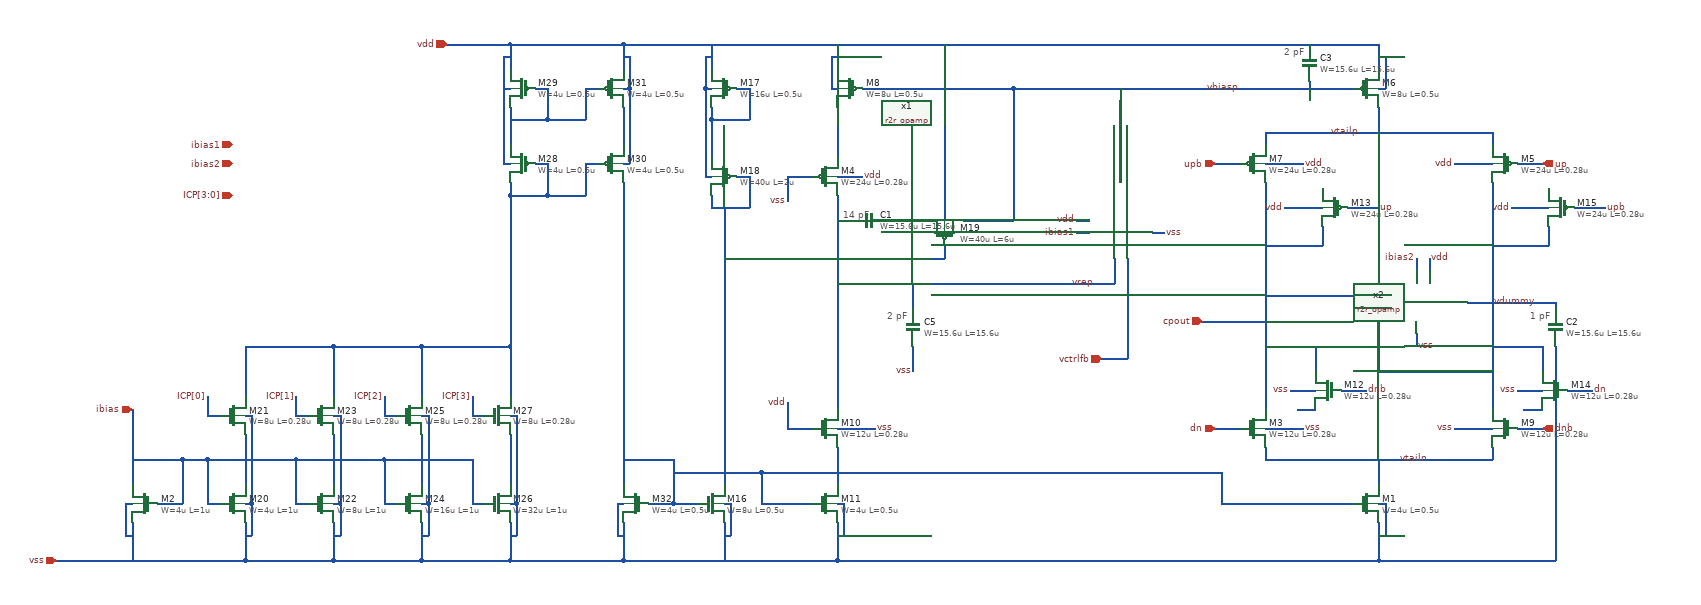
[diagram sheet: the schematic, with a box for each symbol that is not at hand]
v {xschem version=3.4.5 file_version=1.2
}
G {}
K {}
V {}
S {}
E {}
T {2 pF} 1260 -420 0 0 0.2 0.2 {}
T {1 pF} 2280 -420 0 0 0.2 0.2 {}
T {2 pF} 1890 -840 0 0 0.2 0.2 {}
T {14 pF} 1190 -580 0 0 0.2 0.2 {}
N 60 -260 60 -140 {
lab=ibias}
N 1960 -110 2000 -110 {
lab=#net1}
N 60 -80 60 -20 {
lab=vss}
N 2040 -80 2040 -20 {
lab=vss}
N 50 -110 60 -110 {
lab=vss}
N 50 -110 50 -60 {
lab=vss}
N 50 -60 60 -60 {
lab=vss}
N 2040 -110 2050 -110 {
lab=vss}
N 2050 -110 2050 -60 {
lab=vss}
N 2040 -60 2050 -60 {
lab=vss}
N 2040 -840 2040 -800 {
lab=vdd}
N 2040 -770 2050 -770 {
lab=vdd}
N 2050 -820 2050 -770 {
lab=vdd}
N 2040 -820 2050 -820 {
lab=vdd}
N 1940 -770 2000 -770 {
lab=vbiasp}
N 1860 -650 1870 -650 {
lab=vdd}
N -60 -20 20 -20 {
lab=vss}
N 1180 -840 1180 -800 {
lab=vdd}
N 1170 -770 1180 -770 {
lab=vdd}
N 1170 -820 1170 -770 {
lab=vdd}
N 1170 -820 1180 -820 {
lab=vdd}
N 1220 -770 1280 -770 {
lab=vbiasp}
N 1680 -840 2040 -840 {
lab=vdd}
N 1380 -840 1480 -840 {
lab=vdd}
N 1680 -770 1940 -770 {
lab=vbiasp}
N 1280 -840 1380 -840 {
lab=vdd}
N 1480 -840 1680 -840 {
lab=vdd}
N 1480 -770 1680 -770 {
lab=vbiasp}
N 2210 -650 2220 -650 {
lab=vdd}
N 1860 -700 1860 -680 {
lab=vtailp}
N 1860 -700 2220 -700 {
lab=vtailp}
N 2220 -700 2220 -680 {
lab=vtailp}
N 2040 -740 2040 -700 {
lab=vtailp}
N 1870 -650 1920 -650 {
lab=vdd}
N 2160 -650 2210 -650 {
lab=vdd}
N 1860 -200 1860 -180 {
lab=vtailn}
N 1860 -180 2220 -180 {
lab=vtailn}
N 2220 -200 2220 -180 {
lab=vtailn}
N 2040 -180 2040 -140 {
lab=vtailn}
N 1860 -620 1860 -260 {
lab=cpout}
N 2220 -620 2220 -260 {
lab=vdummy}
N 1860 -230 1920 -230 {
lab=vss}
N 2160 -230 2220 -230 {
lab=vss}
N 2180 -430 2220 -430 {
lab=vdummy}
N 2100 -380 2100 -360 {
lab=vss}
N 2100 -500 2100 -480 {
lab=ibias2}
N 2120 -500 2120 -480 {
lab=vdd}
N 1860 -440 2060 -440 {
lab=cpout}
N 2040 -420 2060 -420 {
lab=vdummy}
N 2040 -420 2040 -320 {
lab=vdummy}
N 2040 -320 2220 -320 {
lab=vdummy}
N 1630 -770 1630 -620 {
lab=vbiasp}
N 1180 -630 1190 -630 {
lab=vdd}
N 1180 -230 1240 -230 {
lab=vss}
N 1180 -600 1180 -260 {
lab=vrep}
N 1180 -740 1180 -660 {
lab=#net2}
N 1100 -110 1140 -110 {
lab=#net1}
N 1180 -80 1180 -20 {
lab=vss}
N 1180 -110 1190 -110 {
lab=vss}
N 1190 -110 1190 -60 {
lab=vss}
N 1180 -60 1190 -60 {
lab=vss}
N 1180 -180 1180 -140 {
lab=#net3}
N 1180 -200 1180 -180 {
lab=#net3}
N 1100 -230 1140 -230 {
lab=vdd}
N 1100 -270 1100 -230 {
lab=vdd}
N 1100 -630 1140 -630 {
lab=vss}
N 1100 -630 1100 -590 {
lab=vss}
N 1620 -500 1620 -460 {
lab=vrep}
N 1260 -460 1420 -460 {
lab=vrep}
N 1640 -500 1640 -460 {
lab=vctrlfb}
N 1380 -20 2040 -20 {
lab=vss}
N 1180 -20 1380 -20 {
lab=vss}
N 60 -180 140 -180 {
lab=ibias}
N 140 -180 140 -110 {
lab=ibias}
N 100 -110 140 -110 {
lab=ibias}
N 1060 -110 1100 -110 {
lab=#net1}
N 1060 -160 1590 -160 {
lab=#net1}
N 1790 -160 1790 -110 {
lab=#net1}
N 1790 -110 1960 -110 {
lab=#net1}
N 1900 -290 1940 -290 {
lab=vss}
N 1940 -360 1940 -320 {
lab=cpout}
N 1980 -290 2020 -290 {
lab=dnb}
N 1950 -550 1950 -520 {
lab=cpout}
N 1990 -580 2040 -580 {
lab=up}
N 1890 -580 1950 -580 {
lab=vdd}
N 1780 -230 1820 -230 {
lab=dn}
N 1780 -650 1820 -650 {
lab=upb}
N 2260 -650 2300 -650 {
lab=up}
N 2260 -230 2300 -230 {
lab=dnb}
N 1560 -560 1580 -560 {
lab=vdd}
N 1560 -540 1580 -540 {
lab=ibias1}
N 1680 -540 1700 -540 {
lab=vss}
N 1760 -400 1860 -400 {
lab=cpout}
N 2040 -20 2140 -20 {
lab=vss}
N 2320 -430 2320 -420 {
lab=vdummy}
N 2220 -430 2320 -430 {
lab=vdummy}
N 2320 -360 2320 -20 {
lab=vss}
N 2140 -20 2320 -20 {
lab=vss}
N 1640 -460 1640 -340 {
lab=vctrlfb}
N 1600 -340 1640 -340 {
lab=vctrlfb}
N 1180 -460 1260 -460 {
lab=vrep}
N 1190 -630 1220 -630 {
lab=vdd}
N 1180 -560 1200 -560 {
lab=vrep}
N 1930 -780 1930 -770 {
lab=vbiasp}
N 1910 -260 1940 -260 {
lab=#net4}
N 940 -840 1000 -840 {
lab=vdd}
N 1000 -840 1280 -840 {
lab=vdd}
N 2260 -290 2300 -290 {
lab=vss}
N 2300 -360 2300 -320 {
lab=vdummy}
N 2340 -290 2380 -290 {
lab=dn}
N 2310 -550 2310 -520 {
lab=vdummy}
N 2350 -580 2400 -580 {
lab=upb}
N 2250 -580 2310 -580 {
lab=vdd}
N 2270 -260 2300 -260 {
lab=#net5}
N 1920 -520 1950 -520 {
lab=cpout}
N 2280 -520 2310 -520 {
lab=vdummy}
N 1910 -360 1940 -360 {
lab=cpout}
N 2270 -360 2300 -360 {
lab=vdummy}
N 1860 -360 1910 -360 {
lab=cpout}
N 1860 -520 1920 -520 {
lab=cpout}
N 2220 -520 2280 -520 {
lab=vdummy}
N 2220 -360 2270 -360 {
lab=vdummy}
N 840 -20 1180 -20 {
lab=vss}
N 1590 -160 1790 -160 {
lab=#net1}
N 1420 -460 1620 -460 {
lab=vrep}
N 1000 -80 1000 -20 {
lab=vss}
N 1000 -110 1010 -110 {
lab=vss}
N 1010 -110 1010 -60 {
lab=vss}
N 1000 -60 1010 -60 {
lab=vss}
N 1000 -180 1000 -140 {
lab=#net6}
N 980 -840 980 -800 {
lab=vdd}
N 970 -770 980 -770 {
lab=vdd}
N 970 -820 970 -770 {
lab=vdd}
N 970 -820 980 -820 {
lab=vdd}
N 980 -740 980 -720 {
lab=#net7}
N 980 -720 1040 -720 {
lab=#net7}
N 1040 -770 1040 -720 {
lab=#net7}
N 1020 -770 1040 -770 {
lab=#net7}
N 970 -630 980 -630 {
lab=vdd}
N 980 -600 980 -580 {
lab=#net6}
N 980 -580 1040 -580 {
lab=#net6}
N 1040 -630 1040 -580 {
lab=#net6}
N 1020 -630 1040 -630 {
lab=#net6}
N 980 -720 980 -660 {
lab=#net7}
N 970 -770 970 -630 {
lab=vdd}
N 1000 -580 1000 -180 {
lab=#net6}
N 1380 -560 1460 -560 {
lab=vbiasp}
N 1350 -840 1350 -560 {
lab=vdd}
N 1350 -520 1350 -500 {
lab=#net6}
N 1000 -500 1350 -500 {
lab=#net6}
N 1300 -560 1320 -560 {
lab=#net8}
N 920 -110 960 -110 {
lab=#net1}
N 1060 -160 1060 -110 {
lab=#net1}
N 920 -160 1060 -160 {
lab=#net1}
N 1260 -560 1300 -560 {
lab=#net8}
N 1460 -770 1460 -560 {
lab=vbiasp}
N 1460 -770 1480 -770 {
lab=vbiasp}
N 1280 -770 1460 -770 {
lab=vbiasp}
N 1300 -460 1300 -420 {
lab=vrep}
N 1300 -360 1300 -320 {
lab=vss}
N 180 -180 180 -110 {
lab=ibias}
N 180 -110 200 -110 {
lab=ibias}
N 240 -80 240 -20 {
lab=vss}
N 240 -110 250 -110 {
lab=vss}
N 250 -110 250 -60 {
lab=vss}
N 240 -60 250 -60 {
lab=vss}
N 240 -220 240 -140 {
lab=#net9}
N 240 -250 250 -250 {
lab=vss}
N 250 -250 250 -110 {
lab=vss}
N 240 -360 240 -280 {
lab=#net10}
N 320 -180 320 -110 {
lab=ibias}
N 320 -110 340 -110 {
lab=ibias}
N 380 -80 380 -20 {
lab=vss}
N 380 -110 390 -110 {
lab=vss}
N 390 -110 390 -60 {
lab=vss}
N 380 -60 390 -60 {
lab=vss}
N 380 -220 380 -140 {
lab=#net11}
N 380 -250 390 -250 {
lab=vss}
N 390 -250 390 -110 {
lab=vss}
N 380 -360 380 -280 {
lab=#net10}
N 180 -180 320 -180 {
lab=ibias}
N 460 -180 460 -110 {
lab=ibias}
N 460 -110 480 -110 {
lab=ibias}
N 520 -80 520 -20 {
lab=vss}
N 520 -110 530 -110 {
lab=vss}
N 530 -110 530 -60 {
lab=vss}
N 520 -60 530 -60 {
lab=vss}
N 520 -220 520 -140 {
lab=#net12}
N 520 -250 530 -250 {
lab=vss}
N 530 -250 530 -110 {
lab=vss}
N 520 -360 520 -280 {
lab=#net10}
N 320 -180 460 -180 {
lab=ibias}
N 600 -180 600 -110 {
lab=ibias}
N 600 -110 620 -110 {
lab=ibias}
N 660 -80 660 -20 {
lab=vss}
N 660 -110 670 -110 {
lab=vss}
N 670 -110 670 -60 {
lab=vss}
N 660 -60 670 -60 {
lab=vss}
N 660 -220 660 -140 {
lab=#net13}
N 660 -250 670 -250 {
lab=vss}
N 670 -250 670 -110 {
lab=vss}
N 660 -360 660 -280 {
lab=#net10}
N 460 -180 600 -180 {
lab=ibias}
N 20 -20 240 -20 {
lab=vss}
N 240 -20 380 -20 {
lab=vss}
N 380 -20 520 -20 {
lab=vss}
N 520 -20 660 -20 {
lab=vss}
N 240 -360 380 -360 {
lab=#net10}
N 380 -360 520 -360 {
lab=#net10}
N 520 -360 660 -360 {
lab=#net10}
N 660 -600 720 -600 {
lab=#net10}
N 720 -650 720 -600 {
lab=#net10}
N 700 -650 720 -650 {
lab=#net10}
N 660 -720 720 -720 {
lab=#net14}
N 720 -770 720 -720 {
lab=#net14}
N 700 -770 720 -770 {
lab=#net14}
N 660 -740 660 -680 {
lab=#net14}
N 660 -840 660 -800 {
lab=vdd}
N 650 -650 660 -650 {
lab=vdd}
N 650 -820 650 -650 {
lab=vdd}
N 650 -820 660 -820 {
lab=vdd}
N 650 -770 660 -770 {
lab=vdd}
N 840 -840 840 -800 {
lab=vdd}
N 840 -770 850 -770 {
lab=vdd}
N 850 -820 850 -770 {
lab=vdd}
N 840 -820 850 -820 {
lab=vdd}
N 840 -740 840 -680 {
lab=#net15}
N 840 -650 850 -650 {
lab=vdd}
N 850 -770 850 -650 {
lab=vdd}
N 780 -770 780 -720 {
lab=#net14}
N 780 -770 800 -770 {
lab=#net14}
N 780 -650 780 -600 {
lab=#net10}
N 780 -650 800 -650 {
lab=#net10}
N 840 -260 840 -140 {
lab=#net1}
N 840 -80 840 -20 {
lab=vss}
N 830 -110 840 -110 {
lab=vss}
N 830 -110 830 -60 {
lab=vss}
N 830 -60 840 -60 {
lab=vss}
N 840 -180 920 -180 {
lab=#net1}
N 920 -180 920 -110 {
lab=#net1}
N 880 -110 920 -110 {
lab=#net1}
N 140 -180 180 -180 {
lab=ibias}
N 560 -840 660 -840 {
lab=vdd}
N 660 -840 840 -840 {
lab=vdd}
N 840 -840 940 -840 {
lab=vdd}
N 720 -720 780 -720 {
lab=#net14}
N 720 -600 780 -600 {
lab=#net10}
N 660 -620 660 -600 {
lab=#net10}
N 660 -600 660 -360 {
lab=#net10}
N 840 -620 840 -260 {
lab=#net1}
N 180 -250 200 -250 {
lab=ICP[0]}
N 320 -250 340 -250 {
lab=ICP[1]}
N 460 -250 480 -250 {
lab=ICP[2]}
N 600 -250 620 -250 {
lab=ICP[3]}
N 660 -20 840 -20 {
lab=vss}
N 180 -280 180 -250 {
lab=ICP[0]}
N 320 -280 320 -250 {
lab=ICP[1]}
N 460 -280 460 -250 {
lab=ICP[2]}
N 600 -280 600 -250 {
lab=ICP[3]}
C {symbols/nfet_03v3.sym} 2020 -110 0 0 {name=M1
L=0.5u
W=4u
nf=1
m=1
ad="'int((nf+1)/2) * W/nf * 0.18u'"
pd="'2*int((nf+1)/2) * (W/nf + 0.18u)'"
as="'int((nf+2)/2) * W/nf * 0.18u'"
ps="'2*int((nf+2)/2) * (W/nf + 0.18u)'"
nrd="'0.18u / W'" nrs="'0.18u / W'"
sa=0 sb=0 sd=0
model=nfet_03v3
spiceprefix=X
}
C {symbols/nfet_03v3.sym} 80 -110 0 1 {name=M2
L=1u
W=4u
nf=1
m=1
ad="'int((nf+1)/2) * W/nf * 0.18u'"
pd="'2*int((nf+1)/2) * (W/nf + 0.18u)'"
as="'int((nf+2)/2) * W/nf * 0.18u'"
ps="'2*int((nf+2)/2) * (W/nf + 0.18u)'"
nrd="'0.18u / W'" nrs="'0.18u / W'"
sa=0 sb=0 sd=0
model=nfet_03v3
spiceprefix=X
}
C {symbols/nfet_03v3.sym} 1840 -230 0 0 {name=M3
L=0.28u
W=12u
nf=1
m=1
ad="'int((nf+1)/2) * W/nf * 0.18u'"
pd="'2*int((nf+1)/2) * (W/nf + 0.18u)'"
as="'int((nf+2)/2) * W/nf * 0.18u'"
ps="'2*int((nf+2)/2) * (W/nf + 0.18u)'"
nrd="'0.18u / W'" nrs="'0.18u / W'"
sa=0 sb=0 sd=0
model=nfet_03v3
spiceprefix=X
}
C {symbols/pfet_03v3.sym} 2020 -770 0 0 {name=M6
L=0.5u
W=8u
nf=1
m=1
ad="'int((nf+1)/2) * W/nf * 0.18u'"
pd="'2*int((nf+1)/2) * (W/nf + 0.18u)'"
as="'int((nf+2)/2) * W/nf * 0.18u'"
ps="'2*int((nf+2)/2) * (W/nf + 0.18u)'"
nrd="'0.18u / W'" nrs="'0.18u / W'"
sa=0 sb=0 sd=0
model=pfet_03v3
spiceprefix=X
}
C {symbols/pfet_03v3.sym} 1840 -650 0 0 {name=M7
L=0.28u
W=24u
nf=1
m=1
ad="'int((nf+1)/2) * W/nf * 0.18u'"
pd="'2*int((nf+1)/2) * (W/nf + 0.18u)'"
as="'int((nf+2)/2) * W/nf * 0.18u'"
ps="'2*int((nf+2)/2) * (W/nf + 0.18u)'"
nrd="'0.18u / W'" nrs="'0.18u / W'"
sa=0 sb=0 sd=0
model=pfet_03v3
spiceprefix=X
}
C {ipin.sym} 560 -840 0 0 {name=p1 lab=vdd}
C {ipin.sym} -60 -20 0 0 {name=p2 lab=vss}
C {ipin.sym} 60 -260 1 0 {name=p5 lab=ibias}
C {symbols/pfet_03v3.sym} 1200 -770 0 1 {name=M8
L=0.5u
W=8u
nf=1
m=1
ad="'int((nf+1)/2) * W/nf * 0.18u'"
pd="'2*int((nf+1)/2) * (W/nf + 0.18u)'"
as="'int((nf+2)/2) * W/nf * 0.18u'"
ps="'2*int((nf+2)/2) * (W/nf + 0.18u)'"
nrd="'0.18u / W'" nrs="'0.18u / W'"
sa=0 sb=0 sd=0
model=pfet_03v3
spiceprefix=X
}
C {r2r_opamp.sym} 1680 -500 3 0 {name=x1}
C {symbols/pfet_03v3.sym} 2240 -650 0 1 {name=M5
L=0.28u
W=24u
nf=1
m=1
ad="'int((nf+1)/2) * W/nf * 0.18u'"
pd="'2*int((nf+1)/2) * (W/nf + 0.18u)'"
as="'int((nf+2)/2) * W/nf * 0.18u'"
ps="'2*int((nf+2)/2) * (W/nf + 0.18u)'"
nrd="'0.18u / W'" nrs="'0.18u / W'"
sa=0 sb=0 sd=0
model=pfet_03v3
spiceprefix=X
}
C {symbols/nfet_03v3.sym} 2240 -230 0 1 {name=M9
L=0.28u
W=12u
nf=1
m=1
ad="'int((nf+1)/2) * W/nf * 0.18u'"
pd="'2*int((nf+1)/2) * (W/nf + 0.18u)'"
as="'int((nf+2)/2) * W/nf * 0.18u'"
ps="'2*int((nf+2)/2) * (W/nf + 0.18u)'"
nrd="'0.18u / W'" nrs="'0.18u / W'"
sa=0 sb=0 sd=0
model=nfet_03v3
spiceprefix=X
}
C {r2r_opamp.sym} 2060 -380 0 0 {name=x2}
C {symbols/pfet_03v3.sym} 1160 -630 0 0 {name=M4
L=0.28u
W=24u
nf=1
m=1
ad="'int((nf+1)/2) * W/nf * 0.18u'"
pd="'2*int((nf+1)/2) * (W/nf + 0.18u)'"
as="'int((nf+2)/2) * W/nf * 0.18u'"
ps="'2*int((nf+2)/2) * (W/nf + 0.18u)'"
nrd="'0.18u / W'" nrs="'0.18u / W'"
sa=0 sb=0 sd=0
model=pfet_03v3
spiceprefix=X
}
C {symbols/nfet_03v3.sym} 1160 -230 0 0 {name=M10
L=0.28u
W=12u
nf=1
m=1
ad="'int((nf+1)/2) * W/nf * 0.18u'"
pd="'2*int((nf+1)/2) * (W/nf + 0.18u)'"
as="'int((nf+2)/2) * W/nf * 0.18u'"
ps="'2*int((nf+2)/2) * (W/nf + 0.18u)'"
nrd="'0.18u / W'" nrs="'0.18u / W'"
sa=0 sb=0 sd=0
model=nfet_03v3
spiceprefix=X
}
C {symbols/nfet_03v3.sym} 1160 -110 0 0 {name=M11
L=0.5u
W=4u
nf=1
m=1
ad="'int((nf+1)/2) * W/nf * 0.18u'"
pd="'2*int((nf+1)/2) * (W/nf + 0.18u)'"
as="'int((nf+2)/2) * W/nf * 0.18u'"
ps="'2*int((nf+2)/2) * (W/nf + 0.18u)'"
nrd="'0.18u / W'" nrs="'0.18u / W'"
sa=0 sb=0 sd=0
model=nfet_03v3
spiceprefix=X
}
C {symbols/nfet_03v3.sym} 1960 -290 0 1 {name=M12
L=0.28u
W=12u
nf=1
m=1
ad="'int((nf+1)/2) * W/nf * 0.18u'"
pd="'2*int((nf+1)/2) * (W/nf + 0.18u)'"
as="'int((nf+2)/2) * W/nf * 0.18u'"
ps="'2*int((nf+2)/2) * (W/nf + 0.18u)'"
nrd="'0.18u / W'" nrs="'0.18u / W'"
sa=0 sb=0 sd=0
model=nfet_03v3
spiceprefix=X
}
C {symbols/pfet_03v3.sym} 1970 -580 0 1 {name=M13
L=0.28u
W=24u
nf=1
m=1
ad="'int((nf+1)/2) * W/nf * 0.18u'"
pd="'2*int((nf+1)/2) * (W/nf + 0.18u)'"
as="'int((nf+2)/2) * W/nf * 0.18u'"
ps="'2*int((nf+2)/2) * (W/nf + 0.18u)'"
nrd="'0.18u / W'" nrs="'0.18u / W'"
sa=0 sb=0 sd=0
model=pfet_03v3
spiceprefix=X
}
C {lab_pin.sym} 1100 -590 3 0 {name=p3 sig_type=std_logic lab=vss}
C {lab_pin.sym} 1100 -270 1 0 {name=p4 sig_type=std_logic lab=vdd}
C {lab_pin.sym} 1700 -540 2 0 {name=p6 sig_type=std_logic lab=vss}
C {lab_pin.sym} 1560 -560 0 0 {name=p7 sig_type=std_logic lab=vdd}
C {lab_pin.sym} 1560 -540 0 0 {name=p8 sig_type=std_logic lab=ibias1}
C {lab_pin.sym} 2100 -360 2 0 {name=p9 sig_type=std_logic lab=vss}
C {lab_pin.sym} 2120 -500 0 1 {name=p10 sig_type=std_logic lab=vdd}
C {lab_pin.sym} 2100 -500 0 0 {name=p11 sig_type=std_logic lab=ibias2}
C {lab_pin.sym} 1920 -230 2 0 {name=p12 sig_type=std_logic lab=vss}
C {lab_pin.sym} 1900 -290 2 1 {name=p13 sig_type=std_logic lab=vss}
C {lab_pin.sym} 2160 -230 2 1 {name=p14 sig_type=std_logic lab=vss}
C {lab_pin.sym} 1920 -650 0 1 {name=p15 sig_type=std_logic lab=vdd}
C {lab_pin.sym} 1890 -580 0 0 {name=p16 sig_type=std_logic lab=vdd}
C {lab_pin.sym} 2160 -650 0 0 {name=p17 sig_type=std_logic lab=vdd}
C {ipin.sym} 1780 -230 0 0 {name=p18 lab=dn}
C {ipin.sym} 1780 -650 0 0 {name=p19 lab=upb}
C {ipin.sym} 2300 -650 0 1 {name=p20 lab=up}
C {ipin.sym} 2300 -230 0 1 {name=p21 lab=dnb}
C {lab_pin.sym} 2020 -290 2 0 {name=p22 sig_type=std_logic lab=dnb}
C {lab_pin.sym} 2040 -580 2 0 {name=p23 sig_type=std_logic lab=up}
C {opin.sym} 1760 -400 0 1 {name=p24 lab=cpout}
C {lab_pin.sym} 1240 -230 2 0 {name=p25 sig_type=std_logic lab=vss}
C {lab_pin.sym} 1220 -630 0 1 {name=p26 sig_type=std_logic lab=vdd}
C {ipin.sym} 220 -680 0 0 {name=p27 lab=ibias1
}
C {ipin.sym} 220 -650 0 0 {name=p28 lab=ibias2
}
C {ipin.sym} 1600 -340 0 0 {name=p29 lab=vctrlfb
}
C {lab_wire.sym} 1820 -770 0 0 {name=p30 sig_type=std_logic lab=vbiasp}
C {lab_wire.sym} 2290 -430 0 0 {name=p31 sig_type=std_logic lab=vdummy}
C {lab_wire.sym} 2120 -180 0 0 {name=p32 sig_type=std_logic lab=vtailn}
C {lab_wire.sym} 2010 -700 0 0 {name=p33 sig_type=std_logic lab=vtailp}
C {lab_wire.sym} 1590 -460 0 0 {name=p34 sig_type=std_logic lab=vrep}
C {symbols/nfet_03v3.sym} 2320 -290 0 1 {name=M14
L=0.28u
W=12u
nf=1
m=1
ad="'int((nf+1)/2) * W/nf * 0.18u'"
pd="'2*int((nf+1)/2) * (W/nf + 0.18u)'"
as="'int((nf+2)/2) * W/nf * 0.18u'"
ps="'2*int((nf+2)/2) * (W/nf + 0.18u)'"
nrd="'0.18u / W'" nrs="'0.18u / W'"
sa=0 sb=0 sd=0
model=nfet_03v3
spiceprefix=X
}
C {symbols/pfet_03v3.sym} 2330 -580 0 1 {name=M15
L=0.28u
W=24u
nf=1
m=1
ad="'int((nf+1)/2) * W/nf * 0.18u'"
pd="'2*int((nf+1)/2) * (W/nf + 0.18u)'"
as="'int((nf+2)/2) * W/nf * 0.18u'"
ps="'2*int((nf+2)/2) * (W/nf + 0.18u)'"
nrd="'0.18u / W'" nrs="'0.18u / W'"
sa=0 sb=0 sd=0
model=pfet_03v3
spiceprefix=X
}
C {lab_pin.sym} 2260 -290 2 1 {name=p36 sig_type=std_logic lab=vss}
C {lab_pin.sym} 2250 -580 0 0 {name=p37 sig_type=std_logic lab=vdd}
C {lab_pin.sym} 2380 -290 2 0 {name=p38 sig_type=std_logic lab=dn}
C {lab_pin.sym} 2400 -580 2 0 {name=p39 sig_type=std_logic lab=upb}
C {noconn.sym} 1910 -260 0 0 {name=l1}
C {noconn.sym} 2270 -260 0 0 {name=l2}
C {noconn.sym} 2310 -610 0 0 {name=l3}
C {noconn.sym} 1950 -610 0 0 {name=l4}
C {symbols/nfet_03v3.sym} 980 -110 0 0 {name=M16
L=0.5u
W=8u
nf=1
m=1
ad="'int((nf+1)/2) * W/nf * 0.18u'"
pd="'2*int((nf+1)/2) * (W/nf + 0.18u)'"
as="'int((nf+2)/2) * W/nf * 0.18u'"
ps="'2*int((nf+2)/2) * (W/nf + 0.18u)'"
nrd="'0.18u / W'" nrs="'0.18u / W'"
sa=0 sb=0 sd=0
model=nfet_03v3
spiceprefix=X
}
C {symbols/pfet_03v3.sym} 1000 -770 0 1 {name=M17
L=0.5u
W=16u
nf=1
m=1
ad="'int((nf+1)/2) * W/nf * 0.18u'"
pd="'2*int((nf+1)/2) * (W/nf + 0.18u)'"
as="'int((nf+2)/2) * W/nf * 0.18u'"
ps="'2*int((nf+2)/2) * (W/nf + 0.18u)'"
nrd="'0.18u / W'" nrs="'0.18u / W'"
sa=0 sb=0 sd=0
model=pfet_03v3
spiceprefix=X
}
C {symbols/pfet_03v3.sym} 1000 -630 0 1 {name=M18
L=2u
W=40u
nf=1
m=1
ad="'int((nf+1)/2) * W/nf * 0.18u'"
pd="'2*int((nf+1)/2) * (W/nf + 0.18u)'"
as="'int((nf+2)/2) * W/nf * 0.18u'"
ps="'2*int((nf+2)/2) * (W/nf + 0.18u)'"
nrd="'0.18u / W'" nrs="'0.18u / W'"
sa=0 sb=0 sd=0
model=pfet_03v3
spiceprefix=X
}
C {symbols/pfet_03v3.sym} 1350 -540 1 1 {name=M19
L=6u
W=40u
nf=1
m=1
ad="'int((nf+1)/2) * W/nf * 0.18u'"
pd="'2*int((nf+1)/2) * (W/nf + 0.18u)'"
as="'int((nf+2)/2) * W/nf * 0.18u'"
ps="'2*int((nf+2)/2) * (W/nf + 0.18u)'"
nrd="'0.18u / W'" nrs="'0.18u / W'"
sa=0 sb=0 sd=0
model=pfet_03v3
spiceprefix=X
}
C {lab_pin.sym} 1300 -320 3 0 {name=p35 sig_type=std_logic lab=vss}
C {symbols/nfet_03v3.sym} 220 -110 0 0 {name=M20
L=1u
W=4u
nf=1
m=1
ad="'int((nf+1)/2) * W/nf * 0.18u'"
pd="'2*int((nf+1)/2) * (W/nf + 0.18u)'"
as="'int((nf+2)/2) * W/nf * 0.18u'"
ps="'2*int((nf+2)/2) * (W/nf + 0.18u)'"
nrd="'0.18u / W'" nrs="'0.18u / W'"
sa=0 sb=0 sd=0
model=nfet_03v3
spiceprefix=X
}
C {symbols/nfet_03v3.sym} 220 -250 0 0 {name=M21
L=0.28u
W=8u
nf=1
m=1
ad="'int((nf+1)/2) * W/nf * 0.18u'"
pd="'2*int((nf+1)/2) * (W/nf + 0.18u)'"
as="'int((nf+2)/2) * W/nf * 0.18u'"
ps="'2*int((nf+2)/2) * (W/nf + 0.18u)'"
nrd="'0.18u / W'" nrs="'0.18u / W'"
sa=0 sb=0 sd=0
model=nfet_03v3
spiceprefix=X
}
C {symbols/nfet_03v3.sym} 360 -110 0 0 {name=M22
L=1u
W=8u
nf=1
m=1
ad="'int((nf+1)/2) * W/nf * 0.18u'"
pd="'2*int((nf+1)/2) * (W/nf + 0.18u)'"
as="'int((nf+2)/2) * W/nf * 0.18u'"
ps="'2*int((nf+2)/2) * (W/nf + 0.18u)'"
nrd="'0.18u / W'" nrs="'0.18u / W'"
sa=0 sb=0 sd=0
model=nfet_03v3
spiceprefix=X
}
C {symbols/nfet_03v3.sym} 360 -250 0 0 {name=M23
L=0.28u
W=8u
nf=1
m=1
ad="'int((nf+1)/2) * W/nf * 0.18u'"
pd="'2*int((nf+1)/2) * (W/nf + 0.18u)'"
as="'int((nf+2)/2) * W/nf * 0.18u'"
ps="'2*int((nf+2)/2) * (W/nf + 0.18u)'"
nrd="'0.18u / W'" nrs="'0.18u / W'"
sa=0 sb=0 sd=0
model=nfet_03v3
spiceprefix=X
}
C {symbols/nfet_03v3.sym} 500 -110 0 0 {name=M24
L=1u
W=16u
nf=1
m=1
ad="'int((nf+1)/2) * W/nf * 0.18u'"
pd="'2*int((nf+1)/2) * (W/nf + 0.18u)'"
as="'int((nf+2)/2) * W/nf * 0.18u'"
ps="'2*int((nf+2)/2) * (W/nf + 0.18u)'"
nrd="'0.18u / W'" nrs="'0.18u / W'"
sa=0 sb=0 sd=0
model=nfet_03v3
spiceprefix=X
}
C {symbols/nfet_03v3.sym} 500 -250 0 0 {name=M25
L=0.28u
W=8u
nf=1
m=1
ad="'int((nf+1)/2) * W/nf * 0.18u'"
pd="'2*int((nf+1)/2) * (W/nf + 0.18u)'"
as="'int((nf+2)/2) * W/nf * 0.18u'"
ps="'2*int((nf+2)/2) * (W/nf + 0.18u)'"
nrd="'0.18u / W'" nrs="'0.18u / W'"
sa=0 sb=0 sd=0
model=nfet_03v3
spiceprefix=X
}
C {symbols/nfet_03v3.sym} 640 -110 0 0 {name=M26
L=1u
W=32u
nf=1
m=1
ad="'int((nf+1)/2) * W/nf * 0.18u'"
pd="'2*int((nf+1)/2) * (W/nf + 0.18u)'"
as="'int((nf+2)/2) * W/nf * 0.18u'"
ps="'2*int((nf+2)/2) * (W/nf + 0.18u)'"
nrd="'0.18u / W'" nrs="'0.18u / W'"
sa=0 sb=0 sd=0
model=nfet_03v3
spiceprefix=X
}
C {symbols/nfet_03v3.sym} 640 -250 0 0 {name=M27
L=0.28u
W=8u
nf=1
m=1
ad="'int((nf+1)/2) * W/nf * 0.18u'"
pd="'2*int((nf+1)/2) * (W/nf + 0.18u)'"
as="'int((nf+2)/2) * W/nf * 0.18u'"
ps="'2*int((nf+2)/2) * (W/nf + 0.18u)'"
nrd="'0.18u / W'" nrs="'0.18u / W'"
sa=0 sb=0 sd=0
model=nfet_03v3
spiceprefix=X
}
C {symbols/pfet_03v3.sym} 680 -650 0 1 {name=M28
L=0.5u
W=4u
nf=1
m=1
ad="'int((nf+1)/2) * W/nf * 0.18u'"
pd="'2*int((nf+1)/2) * (W/nf + 0.18u)'"
as="'int((nf+2)/2) * W/nf * 0.18u'"
ps="'2*int((nf+2)/2) * (W/nf + 0.18u)'"
nrd="'0.18u / W'" nrs="'0.18u / W'"
sa=0 sb=0 sd=0
model=pfet_03v3
spiceprefix=X
}
C {symbols/pfet_03v3.sym} 680 -770 0 1 {name=M29
L=0.5u
W=4u
nf=1
m=1
ad="'int((nf+1)/2) * W/nf * 0.18u'"
pd="'2*int((nf+1)/2) * (W/nf + 0.18u)'"
as="'int((nf+2)/2) * W/nf * 0.18u'"
ps="'2*int((nf+2)/2) * (W/nf + 0.18u)'"
nrd="'0.18u / W'" nrs="'0.18u / W'"
sa=0 sb=0 sd=0
model=pfet_03v3
spiceprefix=X
}
C {symbols/pfet_03v3.sym} 820 -650 0 0 {name=M30
L=0.5u
W=4u
nf=1
m=1
ad="'int((nf+1)/2) * W/nf * 0.18u'"
pd="'2*int((nf+1)/2) * (W/nf + 0.18u)'"
as="'int((nf+2)/2) * W/nf * 0.18u'"
ps="'2*int((nf+2)/2) * (W/nf + 0.18u)'"
nrd="'0.18u / W'" nrs="'0.18u / W'"
sa=0 sb=0 sd=0
model=pfet_03v3
spiceprefix=X
}
C {symbols/pfet_03v3.sym} 820 -770 0 0 {name=M31
L=0.5u
W=4u
nf=1
m=1
ad="'int((nf+1)/2) * W/nf * 0.18u'"
pd="'2*int((nf+1)/2) * (W/nf + 0.18u)'"
as="'int((nf+2)/2) * W/nf * 0.18u'"
ps="'2*int((nf+2)/2) * (W/nf + 0.18u)'"
nrd="'0.18u / W'" nrs="'0.18u / W'"
sa=0 sb=0 sd=0
model=pfet_03v3
spiceprefix=X
}
C {symbols/nfet_03v3.sym} 860 -110 0 1 {name=M32
L=0.5u
W=4u
nf=1
m=1
ad="'int((nf+1)/2) * W/nf * 0.18u'"
pd="'2*int((nf+1)/2) * (W/nf + 0.18u)'"
as="'int((nf+2)/2) * W/nf * 0.18u'"
ps="'2*int((nf+2)/2) * (W/nf + 0.18u)'"
nrd="'0.18u / W'" nrs="'0.18u / W'"
sa=0 sb=0 sd=0
model=nfet_03v3
spiceprefix=X
}
C {lab_pin.sym} 180 -280 1 0 {name=p40 sig_type=std_logic lab=ICP[0]}
C {lab_pin.sym} 320 -280 1 0 {name=p41 sig_type=std_logic lab=ICP[1]}
C {lab_pin.sym} 460 -280 1 0 {name=p42 sig_type=std_logic lab=ICP[2]}
C {lab_pin.sym} 600 -280 1 0 {name=p43 sig_type=std_logic lab=ICP[3]}
C {ipin.sym} 220 -600 0 0 {name=p44 lab=ICP[3:0]
}
C {symbols/cap_mim_2f0fF.sym} 1300 -390 0 0 {name=C5
W=15.6u
L=15.6u
model=cap_mim_2f0fF
spiceprefix=X
m=4}
C {symbols/cap_mim_2f0fF.sym} 2320 -390 0 0 {name=C2
W=15.6u
L=15.6u
model=cap_mim_2f0fF
spiceprefix=X
m=2}
C {symbols/cap_mim_2f0fF.sym} 1930 -810 0 0 {name=C3
W=15.6u
L=15.6u
model=cap_mim_2f0fF
spiceprefix=X
m=4}
C {symbols/cap_mim_2f0fF.sym} 1230 -560 1 0 {name=C1
W=15.6u
L=15.6u
model=cap_mim_2f0fF
spiceprefix=X
m=14}
